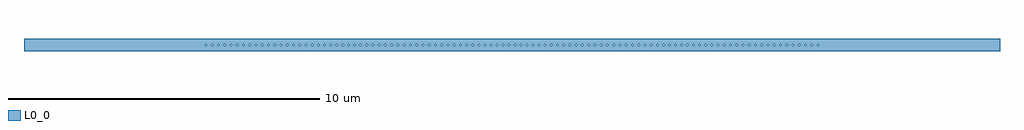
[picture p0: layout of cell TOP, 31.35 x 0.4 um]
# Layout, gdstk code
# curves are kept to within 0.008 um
import gdstk
lib = gdstk.Library(unit=1e-6, precision=1e-09)
def P(c, l, *ps):  # polygons
    for p in ps: c.add(gdstk.Polygon(p, *l))
L0_0 = (0, 0)

top = lib.new_cell('TOP')
P(top, L0_0, [(0,0),(0,0),(0,0),(0,0)],
  [(-8.216,0.031),(-8.192,0),(-8.206,-0.026),(-8.226,-0.032),(-8.255,-0.005),(-8.252,0.015),(-8.226,0.032),(-8.427,0.032),(-8.407,0.026),(-8.393,0),(-8.407,-0.026),(-8.427,-0.032),(-8.456,-0.005),(-8.453,0.015),(-8.427,0.032),(-8.628,0.032),(-8.608,0.026),(-8.594,0),(-8.608,-0.026),(-8.628,-0.032),(-8.657,-0.005),(-8.654,0.015),(-8.628,0.032),(-8.829,0.032),(-8.809,0.026),(-8.795,0),(-8.809,-0.026),(-8.829,-0.032),(-8.858,-0.005),(-8.855,0.015),(-8.829,0.032),(-9.03,0.032),(-9.01,0.026),(-8.996,0),(-9.01,-0.026),(-9.03,-0.032),(-9.059,-0.005),(-9.056,0.015),(-9.03,0.032),(-9.231,0.032),(-9.211,0.026),(-9.197,0),(-9.211,-0.026),(-9.231,-0.032),(-9.26,-0.005),(-9.257,0.015),(-9.231,0.032),(-9.432,0.032),(-9.412,0.026),(-9.398,0),(-9.412,-0.026),(-9.432,-0.032),(-9.461,-0.005),(-9.458,0.015),(-9.432,0.032),(-9.633,0.032),(-9.613,0.026),(-9.599,0),(-9.613,-0.026),(-9.633,-0.032),(-9.662,-0.005),(-9.659,0.015),(-9.633,0.032),(-9.834,0.032),(-9.814,0.026),(-9.8,0),(-9.814,-0.026),(-9.834,-0.032),(-9.863,-0.005),(-9.86,0.015),(-9.834,0.032),(-15.675,0.032),(-15.675,-0.198),(-8.044,-0.198),(-8.044,-0.023),(-8.054,-0.005),(-8.044,0.023),(-8.044,0.198),(-15.675,0.198),(-15.675,0.032)],
  [(-6.41,0.031),(-6.386,0),(-6.393,-0.019),(-6.42,-0.032),(-6.449,-0.005),(-6.446,0.015),(-6.42,0.032),(-6.62,0.032),(-6.592,0.019),(-6.586,0),(-6.592,-0.019),(-6.62,-0.032),(-6.648,-0.005),(-6.639,0.023),(-6.62,0.032),(-6.82,0.032),(-6.792,0.019),(-6.786,0),(-6.792,-0.019),(-6.82,-0.032),(-6.848,-0.005),(-6.839,0.023),(-6.82,0.032),(-7.02,0.032),(-6.993,0.019),(-6.986,0),(-6.993,-0.019),(-7.02,-0.032),(-7.049,-0.005),(-7.046,0.015),(-7.02,0.032),(-7.221,0.032),(-7.201,0.026),(-7.187,0),(-7.201,-0.026),(-7.221,-0.032),(-7.25,-0.005),(-7.247,0.015),(-7.221,0.032),(-7.422,0.032),(-7.402,0.026),(-7.388,0),(-7.402,-0.026),(-7.422,-0.032),(-7.451,-0.005),(-7.448,0.015),(-7.422,0.032),(-7.623,0.032),(-7.603,0.026),(-7.589,0),(-7.603,-0.026),(-7.623,-0.032),(-7.652,-0.005),(-7.649,0.015),(-7.623,0.032),(-7.824,0.032),(-7.804,0.026),(-7.79,0),(-7.804,-0.026),(-7.824,-0.032),(-7.853,-0.005),(-7.85,0.015),(-7.824,0.032),(-8.025,0.032),(-8.005,0.026),(-7.991,0),(-8.015,-0.031),(-8.044,-0.023),(-8.044,-0.198),(-6.222,-0.198),(-6.222,-0.032),(-6.25,-0.005),(-6.241,0.023),(-6.222,0.032),(-6.222,0.198),(-8.044,0.198),(-8.044,0.032)],
  [(-8.035,0.029),(-8.025,0.032),(-8.044,0.032),(-8.044,0.023)],
  [(-4.462,0.031),(-4.462,0.198),(-6.222,0.198),(-6.222,0.032),(-4.473,0.032)],
  [(-4.462,-0.031),(-4.483,-0.029),(-4.501,-0.005),(-4.492,0.023),(-4.473,0.032),(-4.673,0.032),(-4.646,0.019),(-4.639,0),(-4.646,-0.019),(-4.673,-0.032),(-4.702,-0.005),(-4.699,0.015),(-4.673,0.032),(-4.875,0.032),(-4.847,0.019),(-4.84,0),(-4.847,-0.019),(-4.875,-0.032),(-4.903,-0.005),(-4.9,0.015),(-4.875,0.032),(-5.064,0.032),(-5.036,0.019),(-5.029,0),(-5.036,-0.019),(-5.064,-0.032),(-5.092,-0.005),(-5.089,0.015),(-5.064,0.032),(-5.253,0.032),(-5.225,0.019),(-5.219,0),(-5.225,-0.019),(-5.253,-0.032),(-5.281,-0.005),(-5.272,0.023),(-5.253,0.032),(-5.443,0.032),(-5.423,0.026),(-5.409,0),(-5.423,-0.026),(-5.443,-0.032),(-5.472,-0.005),(-5.469,0.015),(-5.443,0.032),(-5.635,0.032),(-5.615,0.026),(-5.601,0),(-5.615,-0.026),(-5.635,-0.032),(-5.664,-0.005),(-5.661,0.015),(-5.635,0.032),(-5.829,0.032),(-5.809,0.026),(-5.795,0),(-5.809,-0.026),(-5.829,-0.032),(-5.858,-0.005),(-5.855,0.015),(-5.829,0.032),(-6.025,0.032),(-5.997,0.019),(-5.991,0),(-5.997,-0.019),(-6.025,-0.032),(-6.053,-0.005),(-6.044,0.023),(-6.025,0.032),(-6.222,0.032),(-6.194,0.019),(-6.188,0),(-6.194,-0.019),(-6.222,-0.032),(-6.222,-0.198),(-4.462,-0.198)],
  [(-2.653,0.031),(-2.644,0.026),(-2.636,0.019),(-2.636,0.198),(-4.462,0.198),(-4.462,0.032),(-2.664,0.032)],
  [(-2.636,-0.019),(-2.664,-0.032),(-2.689,-0.015),(-2.689,0.015),(-2.664,0.032),(-2.864,0.032),(-2.837,0.019),(-2.83,0),(-2.837,-0.019),(-2.864,-0.032),(-2.893,-0.005),(-2.89,0.015),(-2.864,0.032),(-3.065,0.032),(-3.038,0.019),(-3.031,0),(-3.038,-0.019),(-3.065,-0.032),(-3.094,-0.005),(-3.091,0.015),(-3.065,0.032),(-3.266,0.032),(-3.239,0.019),(-3.232,0),(-3.239,-0.019),(-3.266,-0.032),(-3.295,-0.005),(-3.292,0.015),(-3.266,0.032),(-3.468,0.032),(-3.44,0.019),(-3.433,0),(-3.44,-0.019),(-3.468,-0.032),(-3.496,-0.005),(-3.493,0.015),(-3.468,0.032),(-3.668,0.032),(-3.641,0.019),(-3.634,0),(-3.641,-0.019),(-3.668,-0.032),(-3.697,-0.005),(-3.694,0.015),(-3.668,0.032),(-3.869,0.032),(-3.842,0.019),(-3.835,0),(-3.842,-0.019),(-3.869,-0.032),(-3.898,-0.005),(-3.895,0.015),(-3.869,0.032),(-4.071,0.032),(-4.043,0.019),(-4.036,0),(-4.043,-0.019),(-4.071,-0.032),(-4.099,-0.005),(-4.096,0.015),(-4.071,0.032),(-4.271,0.032),(-4.244,0.019),(-4.237,0),(-4.244,-0.019),(-4.271,-0.032),(-4.3,-0.005),(-4.297,0.015),(-4.271,0.032),(-4.462,0.032),(-4.438,0),(-4.462,-0.031),(-4.462,-0.198),(-2.636,-0.198)],
  [(-0.859,0.031),(-0.85,0.026),(-0.842,0.019),(-0.837,0.01),(-0.837,0.198),(-2.636,0.198),(-2.636,0.032),(-0.87,0.032)],
  [(-0.837,-0.01),(-0.859,-0.031),(-0.889,-0.023),(-0.895,0.015),(-0.87,0.032),(-1.065,0.032),(-1.045,0.026),(-1.031,0),(-1.045,-0.026),(-1.065,-0.032),(-1.094,-0.005),(-1.091,0.015),(-1.065,0.032),(-1.262,0.032),(-1.235,0.019),(-1.228,0),(-1.235,-0.019),(-1.262,-0.032),(-1.291,-0.005),(-1.288,0.015),(-1.262,0.032),(-1.461,0.032),(-1.433,0.019),(-1.427,0),(-1.433,-0.019),(-1.461,-0.032),(-1.489,-0.005),(-1.48,0.023),(-1.461,0.032),(-1.661,0.032),(-1.633,0.019),(-1.626,0),(-1.633,-0.019),(-1.661,-0.032),(-1.689,-0.005),(-1.68,0.023),(-1.661,0.032),(-1.86,0.032),(-1.833,0.019),(-1.826,0),(-1.833,-0.019),(-1.86,-0.032),(-1.889,-0.005),(-1.886,0.015),(-1.86,0.032),(-2.061,0.032),(-2.041,0.026),(-2.027,0),(-2.041,-0.026),(-2.061,-0.032),(-2.09,-0.005),(-2.087,0.015),(-2.061,0.032),(-2.262,0.032),(-2.234,0.019),(-2.228,0),(-2.234,-0.019),(-2.262,-0.032),(-2.29,-0.005),(-2.281,0.023),(-2.262,0.032),(-2.463,0.032),(-2.429,0.005),(-2.435,-0.019),(-2.463,-0.032),(-2.491,-0.005),(-2.482,0.023),(-2.463,0.032),(-2.636,0.032),(-2.636,-0.198),(-0.837,-0.198)],
  [(0.875,0.031),(0.884,0.026),(0.892,0.019),(0.897,0.01),(0.897,0.198),(-0.837,0.198),(-0.837,0.032),(0.865,0.032)],
  [(0.897,-0.198),(0.897,-0.01),(0.865,-0.032),(0.836,-0.005),(0.839,0.015),(0.865,0.032),(0.67,0.032),(0.698,0.019),(0.705,0),(0.698,-0.019),(0.67,-0.032),(0.642,-0.005),(0.645,0.015),(0.67,0.032),(0.479,0.032),(0.499,0.026),(0.513,0),(0.499,-0.026),(0.479,-0.032),(0.45,-0.005),(0.453,0.015),(0.479,0.032),(0.288,0.032),(0.316,0.019),(0.322,0),(0.316,-0.019),(0.288,-0.032),(0.26,-0.005),(0.269,0.023),(0.288,0.032),(0.099,0.032),(0.119,0.026),(0.133,0),(0.119,-0.026),(0.099,-0.032),(0.07,-0.005),(0.073,0.015),(0.099,0.032),(-0.104,0.032),(-0.084,0.026),(-0.07,0),(-0.084,-0.026),(-0.104,-0.032),(-0.133,-0.005),(-0.13,0.015),(-0.104,0.032),(-0.293,0.032),(-0.266,0.019),(-0.259,0),(-0.266,-0.019),(-0.293,-0.032),(-0.322,-0.005),(-0.319,0.015),(-0.293,0.032),(-0.484,0.032),(-0.456,0.019),(-0.45,0),(-0.456,-0.019),(-0.484,-0.032),(-0.512,-0.005),(-0.503,0.023),(-0.484,0.032),(-0.676,0.032),(-0.648,0.019),(-0.642,0),(-0.648,-0.019),(-0.676,-0.032),(-0.704,-0.005),(-0.695,0.023),(-0.676,0.032),(-0.837,0.032),(-0.837,-0.198)],
  [(2.669,0.031),(2.691,0.01),(2.691,-0.01),(2.658,-0.032),(2.63,-0.005),(2.639,0.023),(2.658,0.032),(2.457,0.032),(2.485,0.019),(2.492,0),(2.485,-0.019),(2.457,-0.032),(2.429,-0.005),(2.432,0.015),(2.457,0.032),(2.256,0.032),(2.284,0.019),(2.291,0),(2.284,-0.019),(2.256,-0.032),(2.228,-0.005),(2.237,0.023),(2.256,0.032),(2.056,0.032),(2.076,0.026),(2.09,0),(2.076,-0.026),(2.056,-0.032),(2.027,-0.005),(2.03,0.015),(2.056,0.032),(1.855,0.032),(1.883,0.019),(1.889,0),(1.883,-0.019),(1.855,-0.032),(1.827,-0.005),(1.836,0.023),(1.855,0.032),(1.655,0.032),(1.683,0.019),(1.689,0),(1.683,-0.019),(1.655,-0.032),(1.627,-0.005),(1.636,0.023),(1.655,0.032),(1.456,0.032),(1.483,0.019),(1.49,0),(1.483,-0.019),(1.456,-0.032),(1.427,-0.005),(1.43,0.015),(1.456,0.032),(1.257,0.032),(1.285,0.019),(1.291,0),(1.285,-0.019),(1.257,-0.032),(1.229,-0.005),(1.238,0.023),(1.257,0.032),(1.06,0.032),(1.088,0.019),(1.094,0),(1.088,-0.019),(1.06,-0.032),(1.032,-0.005),(1.041,0.023),(1.06,0.032),(0.897,0.032),(0.897,-0.198),(2.692,-0.198),(2.692,0.198),(0.897,0.198),(0.897,0.032)],
  [(4.478,0.031),(4.487,0.026),(4.487,0.198),(2.692,0.198),(2.692,0.032),(4.467,0.032)],
  [(4.487,-0.026),(4.467,-0.032),(4.442,-0.015),(4.442,0.015),(4.467,0.032),(4.266,0.032),(4.294,0.019),(4.3,0),(4.294,-0.019),(4.266,-0.032),(4.238,-0.005),(4.247,0.023),(4.266,0.032),(4.065,0.032),(4.093,0.019),(4.099,0),(4.093,-0.019),(4.065,-0.032),(4.037,-0.005),(4.046,0.023),(4.065,0.032),(3.864,0.032),(3.892,0.019),(3.898,0),(3.892,-0.019),(3.864,-0.032),(3.836,-0.005),(3.845,0.023),(3.864,0.032),(3.663,0.032),(3.691,0.019),(3.697,0),(3.691,-0.019),(3.663,-0.032),(3.635,-0.005),(3.644,0.023),(3.663,0.032),(3.462,0.032),(3.49,0.019),(3.496,0),(3.49,-0.019),(3.462,-0.032),(3.434,-0.005),(3.443,0.023),(3.462,0.032),(3.261,0.032),(3.289,0.019),(3.295,0),(3.289,-0.019),(3.261,-0.032),(3.233,-0.005),(3.242,0.023),(3.261,0.032),(3.06,0.032),(3.088,0.019),(3.094,0),(3.088,-0.019),(3.06,-0.032),(3.032,-0.005),(3.041,0.023),(3.06,0.032),(2.859,0.032),(2.887,0.019),(2.893,0),(2.887,-0.019),(2.859,-0.032),(2.831,-0.005),(2.84,0.023),(2.859,0.032),(2.692,0.032),(2.692,-0.198),(4.487,-0.198)],
  [(6.03,0.031),(6.054,0),(6.047,-0.019),(6.02,-0.032),(5.991,-0.005),(5.994,0.015),(6.02,0.032),(5.824,0.032),(5.844,0.026),(5.858,0),(5.844,-0.026),(5.824,-0.032),(5.795,-0.005),(5.798,0.015),(5.824,0.032),(5.63,0.032),(5.658,0.019),(5.664,0),(5.658,-0.019),(5.63,-0.032),(5.602,-0.005),(5.611,0.023),(5.63,0.032),(5.438,0.032),(5.466,0.019),(5.472,0),(5.466,-0.019),(5.438,-0.032),(5.41,-0.005),(5.419,0.023),(5.438,0.032),(5.248,0.032),(5.268,0.026),(5.282,0),(5.268,-0.026),(5.248,-0.032),(5.219,-0.005),(5.222,0.015),(5.248,0.032),(5.058,0.032),(5.086,0.019),(5.092,0),(5.086,-0.019),(5.058,-0.032),(5.03,-0.005),(5.039,0.023),(5.058,0.032),(4.869,0.032),(4.897,0.019),(4.903,0),(4.897,-0.019),(4.869,-0.032),(4.841,-0.005),(4.85,0.023),(4.869,0.032),(4.668,0.032),(4.696,0.019),(4.702,0),(4.696,-0.019),(4.668,-0.032),(4.64,-0.005),(4.649,0.023),(4.668,0.032),(4.487,0.032),(4.501,0),(4.487,-0.026),(4.487,-0.198),(6.217,-0.198),(6.217,-0.032),(6.188,-0.005),(6.191,0.015),(6.217,0.032),(6.217,0.198),(4.487,0.198),(4.487,0.032)],
  [(8.03,0.031),(8.04,0.026),(8.047,0.019),(8.047,0.198),(6.217,0.198),(6.217,0.032),(8.02,0.032)],
  [(8.047,-0.019),(8.02,-0.032),(7.994,-0.015),(7.994,0.015),(8.02,0.032),(7.819,0.032),(7.839,0.026),(7.853,0),(7.839,-0.026),(7.819,-0.032),(7.79,-0.005),(7.793,0.015),(7.819,0.032),(7.618,0.032),(7.638,0.026),(7.652,0),(7.638,-0.026),(7.618,-0.032),(7.589,-0.005),(7.592,0.015),(7.618,0.032),(7.417,0.032),(7.437,0.026),(7.451,0),(7.437,-0.026),(7.417,-0.032),(7.388,-0.005),(7.391,0.015),(7.417,0.032),(7.216,0.032),(7.244,0.019),(7.25,0),(7.244,-0.019),(7.216,-0.032),(7.188,-0.005),(7.19,0.015),(7.216,0.032),(7.015,0.032),(7.043,0.019),(7.049,0),(7.043,-0.019),(7.015,-0.032),(6.987,-0.005),(6.996,0.023),(7.015,0.032),(6.815,0.032),(6.835,0.026),(6.849,0),(6.835,-0.026),(6.815,-0.032),(6.786,-0.005),(6.789,0.015),(6.815,0.032),(6.615,0.032),(6.635,0.026),(6.649,0),(6.635,-0.026),(6.615,-0.032),(6.586,-0.005),(6.589,0.015),(6.615,0.032),(6.415,0.032),(6.443,0.019),(6.449,0),(6.443,-0.019),(6.415,-0.032),(6.387,-0.005),(6.396,0.023),(6.415,0.032),(6.217,0.032),(6.237,0.026),(6.251,0),(6.237,-0.026),(6.217,-0.032),(6.217,-0.198),(8.047,-0.198)],
  [(8.052,0.01),(8.053,-0.005),(8.192,-0.005),(8.195,0.015),(8.221,0.032),(8.248,0.019),(8.254,-0.005),(8.393,-0.005),(8.396,0.015),(8.422,0.032),(8.449,0.019),(8.455,-0.005),(8.594,-0.005),(8.597,0.015),(8.623,0.032),(8.65,0.019),(8.656,-0.005),(8.795,-0.005),(8.798,0.015),(8.824,0.032),(8.844,0.026),(8.858,0),(8.844,-0.026),(8.824,-0.032),(8.795,-0.005),(8.656,-0.005),(8.643,-0.026),(8.623,-0.032),(8.594,-0.005),(8.455,-0.005),(8.442,-0.026),(8.422,-0.032),(8.393,-0.005),(8.254,-0.005),(8.241,-0.026),(8.221,-0.032),(8.192,-0.005),(8.053,-0.005),(8.047,-0.198),(9.014,-0.198),(9.014,-0.029),(8.996,-0.005),(9.014,0.029),(9.014,0.198),(8.047,0.198)],
  [(9.035,0.031),(9.058,-0.005),(9.197,-0.005),(9.2,0.015),(9.226,0.032),(9.253,0.019),(9.259,-0.005),(9.398,-0.005),(9.401,0.015),(9.427,0.032),(9.454,0.019),(9.46,-0.005),(9.599,-0.005),(9.602,0.015),(9.628,0.032),(9.655,0.019),(9.661,-0.005),(9.8,-0.005),(9.803,0.015),(9.829,0.032),(9.849,0.026),(9.863,0),(9.849,-0.026),(9.829,-0.032),(9.8,-0.005),(9.661,-0.005),(9.648,-0.026),(9.628,-0.032),(9.599,-0.005),(9.46,-0.005),(9.447,-0.026),(9.427,-0.032),(9.398,-0.005),(9.259,-0.005),(9.246,-0.026),(9.226,-0.032),(9.197,-0.005),(9.058,-0.005),(9.045,-0.026),(9.014,-0.029),(9.014,-0.198),(15.675,-0.198),(15.675,0.198),(9.014,0.198),(9.014,0.029)])

lib.write_gds('TOP.gds')
